VERSION 5.7 ;
BUSBITCHARS "[]" ;
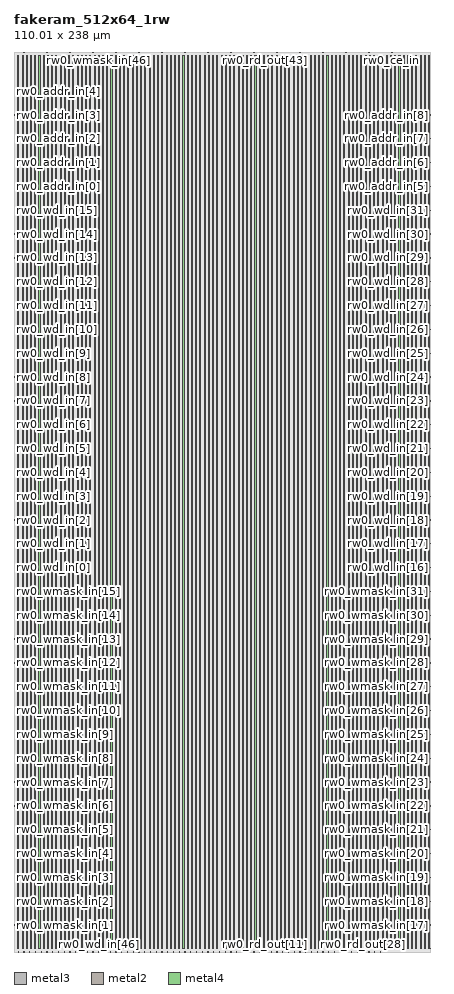
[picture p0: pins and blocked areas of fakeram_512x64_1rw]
MACRO fakeram_512x64_1rw
  FOREIGN fakeram_512x64_1rw 0 0 ;
  SYMMETRY X Y R90 ;
  SIZE 110.010 BY 238.000 ;
  CLASS BLOCK ;
  PIN rw0_wmask_in[0]
    DIRECTION INPUT ;
    USE SIGNAL ;
    SHAPE ABUTMENT ;
    PORT
      LAYER metal3 ;
      RECT 0.000 0.805 0.210 0.875 ;
    END
  END rw0_wmask_in[0]
  PIN rw0_wmask_in[1]
    DIRECTION INPUT ;
    USE SIGNAL ;
    SHAPE ABUTMENT ;
    PORT
      LAYER metal3 ;
      RECT 0.000 7.105 0.210 7.175 ;
    END
  END rw0_wmask_in[1]
  PIN rw0_wmask_in[2]
    DIRECTION INPUT ;
    USE SIGNAL ;
    SHAPE ABUTMENT ;
    PORT
      LAYER metal3 ;
      RECT 0.000 13.405 0.210 13.475 ;
    END
  END rw0_wmask_in[2]
  PIN rw0_wmask_in[3]
    DIRECTION INPUT ;
    USE SIGNAL ;
    SHAPE ABUTMENT ;
    PORT
      LAYER metal3 ;
      RECT 0.000 19.705 0.210 19.775 ;
    END
  END rw0_wmask_in[3]
  PIN rw0_wmask_in[4]
    DIRECTION INPUT ;
    USE SIGNAL ;
    SHAPE ABUTMENT ;
    PORT
      LAYER metal3 ;
      RECT 0.000 26.005 0.210 26.075 ;
    END
  END rw0_wmask_in[4]
  PIN rw0_wmask_in[5]
    DIRECTION INPUT ;
    USE SIGNAL ;
    SHAPE ABUTMENT ;
    PORT
      LAYER metal3 ;
      RECT 0.000 32.305 0.210 32.375 ;
    END
  END rw0_wmask_in[5]
  PIN rw0_wmask_in[6]
    DIRECTION INPUT ;
    USE SIGNAL ;
    SHAPE ABUTMENT ;
    PORT
      LAYER metal3 ;
      RECT 0.000 38.605 0.210 38.675 ;
    END
  END rw0_wmask_in[6]
  PIN rw0_wmask_in[7]
    DIRECTION INPUT ;
    USE SIGNAL ;
    SHAPE ABUTMENT ;
    PORT
      LAYER metal3 ;
      RECT 0.000 44.905 0.210 44.975 ;
    END
  END rw0_wmask_in[7]
  PIN rw0_wmask_in[8]
    DIRECTION INPUT ;
    USE SIGNAL ;
    SHAPE ABUTMENT ;
    PORT
      LAYER metal3 ;
      RECT 0.000 51.205 0.210 51.275 ;
    END
  END rw0_wmask_in[8]
  PIN rw0_wmask_in[9]
    DIRECTION INPUT ;
    USE SIGNAL ;
    SHAPE ABUTMENT ;
    PORT
      LAYER metal3 ;
      RECT 0.000 57.505 0.210 57.575 ;
    END
  END rw0_wmask_in[9]
  PIN rw0_wmask_in[10]
    DIRECTION INPUT ;
    USE SIGNAL ;
    SHAPE ABUTMENT ;
    PORT
      LAYER metal3 ;
      RECT 0.000 63.805 0.210 63.875 ;
    END
  END rw0_wmask_in[10]
  PIN rw0_wmask_in[11]
    DIRECTION INPUT ;
    USE SIGNAL ;
    SHAPE ABUTMENT ;
    PORT
      LAYER metal3 ;
      RECT 0.000 70.105 0.210 70.175 ;
    END
  END rw0_wmask_in[11]
  PIN rw0_wmask_in[12]
    DIRECTION INPUT ;
    USE SIGNAL ;
    SHAPE ABUTMENT ;
    PORT
      LAYER metal3 ;
      RECT 0.000 76.405 0.210 76.475 ;
    END
  END rw0_wmask_in[12]
  PIN rw0_wmask_in[13]
    DIRECTION INPUT ;
    USE SIGNAL ;
    SHAPE ABUTMENT ;
    PORT
      LAYER metal3 ;
      RECT 0.000 82.705 0.210 82.775 ;
    END
  END rw0_wmask_in[13]
  PIN rw0_wmask_in[14]
    DIRECTION INPUT ;
    USE SIGNAL ;
    SHAPE ABUTMENT ;
    PORT
      LAYER metal3 ;
      RECT 0.000 89.005 0.210 89.075 ;
    END
  END rw0_wmask_in[14]
  PIN rw0_wmask_in[15]
    DIRECTION INPUT ;
    USE SIGNAL ;
    SHAPE ABUTMENT ;
    PORT
      LAYER metal3 ;
      RECT 0.000 95.305 0.210 95.375 ;
    END
  END rw0_wmask_in[15]
  PIN rw0_wmask_in[16]
    DIRECTION INPUT ;
    USE SIGNAL ;
    SHAPE ABUTMENT ;
    PORT
      LAYER metal3 ;
      RECT 109.800 0.805 110.010 0.875 ;
    END
  END rw0_wmask_in[16]
  PIN rw0_wmask_in[17]
    DIRECTION INPUT ;
    USE SIGNAL ;
    SHAPE ABUTMENT ;
    PORT
      LAYER metal3 ;
      RECT 109.800 7.105 110.010 7.175 ;
    END
  END rw0_wmask_in[17]
  PIN rw0_wmask_in[18]
    DIRECTION INPUT ;
    USE SIGNAL ;
    SHAPE ABUTMENT ;
    PORT
      LAYER metal3 ;
      RECT 109.800 13.405 110.010 13.475 ;
    END
  END rw0_wmask_in[18]
  PIN rw0_wmask_in[19]
    DIRECTION INPUT ;
    USE SIGNAL ;
    SHAPE ABUTMENT ;
    PORT
      LAYER metal3 ;
      RECT 109.800 19.705 110.010 19.775 ;
    END
  END rw0_wmask_in[19]
  PIN rw0_wmask_in[20]
    DIRECTION INPUT ;
    USE SIGNAL ;
    SHAPE ABUTMENT ;
    PORT
      LAYER metal3 ;
      RECT 109.800 26.005 110.010 26.075 ;
    END
  END rw0_wmask_in[20]
  PIN rw0_wmask_in[21]
    DIRECTION INPUT ;
    USE SIGNAL ;
    SHAPE ABUTMENT ;
    PORT
      LAYER metal3 ;
      RECT 109.800 32.305 110.010 32.375 ;
    END
  END rw0_wmask_in[21]
  PIN rw0_wmask_in[22]
    DIRECTION INPUT ;
    USE SIGNAL ;
    SHAPE ABUTMENT ;
    PORT
      LAYER metal3 ;
      RECT 109.800 38.605 110.010 38.675 ;
    END
  END rw0_wmask_in[22]
  PIN rw0_wmask_in[23]
    DIRECTION INPUT ;
    USE SIGNAL ;
    SHAPE ABUTMENT ;
    PORT
      LAYER metal3 ;
      RECT 109.800 44.905 110.010 44.975 ;
    END
  END rw0_wmask_in[23]
  PIN rw0_wmask_in[24]
    DIRECTION INPUT ;
    USE SIGNAL ;
    SHAPE ABUTMENT ;
    PORT
      LAYER metal3 ;
      RECT 109.800 51.205 110.010 51.275 ;
    END
  END rw0_wmask_in[24]
  PIN rw0_wmask_in[25]
    DIRECTION INPUT ;
    USE SIGNAL ;
    SHAPE ABUTMENT ;
    PORT
      LAYER metal3 ;
      RECT 109.800 57.505 110.010 57.575 ;
    END
  END rw0_wmask_in[25]
  PIN rw0_wmask_in[26]
    DIRECTION INPUT ;
    USE SIGNAL ;
    SHAPE ABUTMENT ;
    PORT
      LAYER metal3 ;
      RECT 109.800 63.805 110.010 63.875 ;
    END
  END rw0_wmask_in[26]
  PIN rw0_wmask_in[27]
    DIRECTION INPUT ;
    USE SIGNAL ;
    SHAPE ABUTMENT ;
    PORT
      LAYER metal3 ;
      RECT 109.800 70.105 110.010 70.175 ;
    END
  END rw0_wmask_in[27]
  PIN rw0_wmask_in[28]
    DIRECTION INPUT ;
    USE SIGNAL ;
    SHAPE ABUTMENT ;
    PORT
      LAYER metal3 ;
      RECT 109.800 76.405 110.010 76.475 ;
    END
  END rw0_wmask_in[28]
  PIN rw0_wmask_in[29]
    DIRECTION INPUT ;
    USE SIGNAL ;
    SHAPE ABUTMENT ;
    PORT
      LAYER metal3 ;
      RECT 109.800 82.705 110.010 82.775 ;
    END
  END rw0_wmask_in[29]
  PIN rw0_wmask_in[30]
    DIRECTION INPUT ;
    USE SIGNAL ;
    SHAPE ABUTMENT ;
    PORT
      LAYER metal3 ;
      RECT 109.800 89.005 110.010 89.075 ;
    END
  END rw0_wmask_in[30]
  PIN rw0_wmask_in[31]
    DIRECTION INPUT ;
    USE SIGNAL ;
    SHAPE ABUTMENT ;
    PORT
      LAYER metal3 ;
      RECT 109.800 95.305 110.010 95.375 ;
    END
  END rw0_wmask_in[31]
  PIN rw0_wmask_in[32]
    DIRECTION INPUT ;
    USE SIGNAL ;
    SHAPE ABUTMENT ;
    PORT
      LAYER metal2 ;
      RECT 1.105 237.790 1.175 238.000 ;
    END
  END rw0_wmask_in[32]
  PIN rw0_wmask_in[33]
    DIRECTION INPUT ;
    USE SIGNAL ;
    SHAPE ABUTMENT ;
    PORT
      LAYER metal2 ;
      RECT 2.625 237.790 2.695 238.000 ;
    END
  END rw0_wmask_in[33]
  PIN rw0_wmask_in[34]
    DIRECTION INPUT ;
    USE SIGNAL ;
    SHAPE ABUTMENT ;
    PORT
      LAYER metal2 ;
      RECT 4.145 237.790 4.215 238.000 ;
    END
  END rw0_wmask_in[34]
  PIN rw0_wmask_in[35]
    DIRECTION INPUT ;
    USE SIGNAL ;
    SHAPE ABUTMENT ;
    PORT
      LAYER metal2 ;
      RECT 5.665 237.790 5.735 238.000 ;
    END
  END rw0_wmask_in[35]
  PIN rw0_wmask_in[36]
    DIRECTION INPUT ;
    USE SIGNAL ;
    SHAPE ABUTMENT ;
    PORT
      LAYER metal2 ;
      RECT 7.185 237.790 7.255 238.000 ;
    END
  END rw0_wmask_in[36]
  PIN rw0_wmask_in[37]
    DIRECTION INPUT ;
    USE SIGNAL ;
    SHAPE ABUTMENT ;
    PORT
      LAYER metal2 ;
      RECT 8.705 237.790 8.775 238.000 ;
    END
  END rw0_wmask_in[37]
  PIN rw0_wmask_in[38]
    DIRECTION INPUT ;
    USE SIGNAL ;
    SHAPE ABUTMENT ;
    PORT
      LAYER metal2 ;
      RECT 10.225 237.790 10.295 238.000 ;
    END
  END rw0_wmask_in[38]
  PIN rw0_wmask_in[39]
    DIRECTION INPUT ;
    USE SIGNAL ;
    SHAPE ABUTMENT ;
    PORT
      LAYER metal2 ;
      RECT 11.745 237.790 11.815 238.000 ;
    END
  END rw0_wmask_in[39]
  PIN rw0_wmask_in[40]
    DIRECTION INPUT ;
    USE SIGNAL ;
    SHAPE ABUTMENT ;
    PORT
      LAYER metal2 ;
      RECT 13.265 237.790 13.335 238.000 ;
    END
  END rw0_wmask_in[40]
  PIN rw0_wmask_in[41]
    DIRECTION INPUT ;
    USE SIGNAL ;
    SHAPE ABUTMENT ;
    PORT
      LAYER metal2 ;
      RECT 14.785 237.790 14.855 238.000 ;
    END
  END rw0_wmask_in[41]
  PIN rw0_wmask_in[42]
    DIRECTION INPUT ;
    USE SIGNAL ;
    SHAPE ABUTMENT ;
    PORT
      LAYER metal2 ;
      RECT 16.305 237.790 16.375 238.000 ;
    END
  END rw0_wmask_in[42]
  PIN rw0_wmask_in[43]
    DIRECTION INPUT ;
    USE SIGNAL ;
    SHAPE ABUTMENT ;
    PORT
      LAYER metal2 ;
      RECT 17.825 237.790 17.895 238.000 ;
    END
  END rw0_wmask_in[43]
  PIN rw0_wmask_in[44]
    DIRECTION INPUT ;
    USE SIGNAL ;
    SHAPE ABUTMENT ;
    PORT
      LAYER metal2 ;
      RECT 19.345 237.790 19.415 238.000 ;
    END
  END rw0_wmask_in[44]
  PIN rw0_wmask_in[45]
    DIRECTION INPUT ;
    USE SIGNAL ;
    SHAPE ABUTMENT ;
    PORT
      LAYER metal2 ;
      RECT 20.865 237.790 20.935 238.000 ;
    END
  END rw0_wmask_in[45]
  PIN rw0_wmask_in[46]
    DIRECTION INPUT ;
    USE SIGNAL ;
    SHAPE ABUTMENT ;
    PORT
      LAYER metal2 ;
      RECT 22.385 237.790 22.455 238.000 ;
    END
  END rw0_wmask_in[46]
  PIN rw0_wmask_in[47]
    DIRECTION INPUT ;
    USE SIGNAL ;
    SHAPE ABUTMENT ;
    PORT
      LAYER metal2 ;
      RECT 23.905 237.790 23.975 238.000 ;
    END
  END rw0_wmask_in[47]
  PIN rw0_wmask_in[48]
    DIRECTION INPUT ;
    USE SIGNAL ;
    SHAPE ABUTMENT ;
    PORT
      LAYER metal2 ;
      RECT 25.425 237.790 25.495 238.000 ;
    END
  END rw0_wmask_in[48]
  PIN rw0_wmask_in[49]
    DIRECTION INPUT ;
    USE SIGNAL ;
    SHAPE ABUTMENT ;
    PORT
      LAYER metal2 ;
      RECT 26.945 237.790 27.015 238.000 ;
    END
  END rw0_wmask_in[49]
  PIN rw0_wmask_in[50]
    DIRECTION INPUT ;
    USE SIGNAL ;
    SHAPE ABUTMENT ;
    PORT
      LAYER metal2 ;
      RECT 28.465 237.790 28.535 238.000 ;
    END
  END rw0_wmask_in[50]
  PIN rw0_wmask_in[51]
    DIRECTION INPUT ;
    USE SIGNAL ;
    SHAPE ABUTMENT ;
    PORT
      LAYER metal2 ;
      RECT 29.985 237.790 30.055 238.000 ;
    END
  END rw0_wmask_in[51]
  PIN rw0_wmask_in[52]
    DIRECTION INPUT ;
    USE SIGNAL ;
    SHAPE ABUTMENT ;
    PORT
      LAYER metal2 ;
      RECT 31.505 237.790 31.575 238.000 ;
    END
  END rw0_wmask_in[52]
  PIN rw0_wmask_in[53]
    DIRECTION INPUT ;
    USE SIGNAL ;
    SHAPE ABUTMENT ;
    PORT
      LAYER metal2 ;
      RECT 33.025 237.790 33.095 238.000 ;
    END
  END rw0_wmask_in[53]
  PIN rw0_wmask_in[54]
    DIRECTION INPUT ;
    USE SIGNAL ;
    SHAPE ABUTMENT ;
    PORT
      LAYER metal2 ;
      RECT 34.545 237.790 34.615 238.000 ;
    END
  END rw0_wmask_in[54]
  PIN rw0_wmask_in[55]
    DIRECTION INPUT ;
    USE SIGNAL ;
    SHAPE ABUTMENT ;
    PORT
      LAYER metal2 ;
      RECT 36.065 237.790 36.135 238.000 ;
    END
  END rw0_wmask_in[55]
  PIN rw0_wmask_in[56]
    DIRECTION INPUT ;
    USE SIGNAL ;
    SHAPE ABUTMENT ;
    PORT
      LAYER metal2 ;
      RECT 37.585 237.790 37.655 238.000 ;
    END
  END rw0_wmask_in[56]
  PIN rw0_wmask_in[57]
    DIRECTION INPUT ;
    USE SIGNAL ;
    SHAPE ABUTMENT ;
    PORT
      LAYER metal2 ;
      RECT 39.105 237.790 39.175 238.000 ;
    END
  END rw0_wmask_in[57]
  PIN rw0_wmask_in[58]
    DIRECTION INPUT ;
    USE SIGNAL ;
    SHAPE ABUTMENT ;
    PORT
      LAYER metal2 ;
      RECT 40.625 237.790 40.695 238.000 ;
    END
  END rw0_wmask_in[58]
  PIN rw0_wmask_in[59]
    DIRECTION INPUT ;
    USE SIGNAL ;
    SHAPE ABUTMENT ;
    PORT
      LAYER metal2 ;
      RECT 42.145 237.790 42.215 238.000 ;
    END
  END rw0_wmask_in[59]
  PIN rw0_wmask_in[60]
    DIRECTION INPUT ;
    USE SIGNAL ;
    SHAPE ABUTMENT ;
    PORT
      LAYER metal2 ;
      RECT 43.665 237.790 43.735 238.000 ;
    END
  END rw0_wmask_in[60]
  PIN rw0_wmask_in[61]
    DIRECTION INPUT ;
    USE SIGNAL ;
    SHAPE ABUTMENT ;
    PORT
      LAYER metal2 ;
      RECT 45.185 237.790 45.255 238.000 ;
    END
  END rw0_wmask_in[61]
  PIN rw0_wmask_in[62]
    DIRECTION INPUT ;
    USE SIGNAL ;
    SHAPE ABUTMENT ;
    PORT
      LAYER metal2 ;
      RECT 46.705 237.790 46.775 238.000 ;
    END
  END rw0_wmask_in[62]
  PIN rw0_wmask_in[63]
    DIRECTION INPUT ;
    USE SIGNAL ;
    SHAPE ABUTMENT ;
    PORT
      LAYER metal2 ;
      RECT 48.225 237.790 48.295 238.000 ;
    END
  END rw0_wmask_in[63]
  PIN rw0_wd_in[0]
    DIRECTION INPUT ;
    USE SIGNAL ;
    SHAPE ABUTMENT ;
    PORT
      LAYER metal3 ;
      RECT 0.000 101.605 0.210 101.675 ;
    END
  END rw0_wd_in[0]
  PIN rw0_wd_in[1]
    DIRECTION INPUT ;
    USE SIGNAL ;
    SHAPE ABUTMENT ;
    PORT
      LAYER metal3 ;
      RECT 0.000 107.905 0.210 107.975 ;
    END
  END rw0_wd_in[1]
  PIN rw0_wd_in[2]
    DIRECTION INPUT ;
    USE SIGNAL ;
    SHAPE ABUTMENT ;
    PORT
      LAYER metal3 ;
      RECT 0.000 114.205 0.210 114.275 ;
    END
  END rw0_wd_in[2]
  PIN rw0_wd_in[3]
    DIRECTION INPUT ;
    USE SIGNAL ;
    SHAPE ABUTMENT ;
    PORT
      LAYER metal3 ;
      RECT 0.000 120.505 0.210 120.575 ;
    END
  END rw0_wd_in[3]
  PIN rw0_wd_in[4]
    DIRECTION INPUT ;
    USE SIGNAL ;
    SHAPE ABUTMENT ;
    PORT
      LAYER metal3 ;
      RECT 0.000 126.805 0.210 126.875 ;
    END
  END rw0_wd_in[4]
  PIN rw0_wd_in[5]
    DIRECTION INPUT ;
    USE SIGNAL ;
    SHAPE ABUTMENT ;
    PORT
      LAYER metal3 ;
      RECT 0.000 133.105 0.210 133.175 ;
    END
  END rw0_wd_in[5]
  PIN rw0_wd_in[6]
    DIRECTION INPUT ;
    USE SIGNAL ;
    SHAPE ABUTMENT ;
    PORT
      LAYER metal3 ;
      RECT 0.000 139.405 0.210 139.475 ;
    END
  END rw0_wd_in[6]
  PIN rw0_wd_in[7]
    DIRECTION INPUT ;
    USE SIGNAL ;
    SHAPE ABUTMENT ;
    PORT
      LAYER metal3 ;
      RECT 0.000 145.705 0.210 145.775 ;
    END
  END rw0_wd_in[7]
  PIN rw0_wd_in[8]
    DIRECTION INPUT ;
    USE SIGNAL ;
    SHAPE ABUTMENT ;
    PORT
      LAYER metal3 ;
      RECT 0.000 152.005 0.210 152.075 ;
    END
  END rw0_wd_in[8]
  PIN rw0_wd_in[9]
    DIRECTION INPUT ;
    USE SIGNAL ;
    SHAPE ABUTMENT ;
    PORT
      LAYER metal3 ;
      RECT 0.000 158.305 0.210 158.375 ;
    END
  END rw0_wd_in[9]
  PIN rw0_wd_in[10]
    DIRECTION INPUT ;
    USE SIGNAL ;
    SHAPE ABUTMENT ;
    PORT
      LAYER metal3 ;
      RECT 0.000 164.605 0.210 164.675 ;
    END
  END rw0_wd_in[10]
  PIN rw0_wd_in[11]
    DIRECTION INPUT ;
    USE SIGNAL ;
    SHAPE ABUTMENT ;
    PORT
      LAYER metal3 ;
      RECT 0.000 170.905 0.210 170.975 ;
    END
  END rw0_wd_in[11]
  PIN rw0_wd_in[12]
    DIRECTION INPUT ;
    USE SIGNAL ;
    SHAPE ABUTMENT ;
    PORT
      LAYER metal3 ;
      RECT 0.000 177.205 0.210 177.275 ;
    END
  END rw0_wd_in[12]
  PIN rw0_wd_in[13]
    DIRECTION INPUT ;
    USE SIGNAL ;
    SHAPE ABUTMENT ;
    PORT
      LAYER metal3 ;
      RECT 0.000 183.505 0.210 183.575 ;
    END
  END rw0_wd_in[13]
  PIN rw0_wd_in[14]
    DIRECTION INPUT ;
    USE SIGNAL ;
    SHAPE ABUTMENT ;
    PORT
      LAYER metal3 ;
      RECT 0.000 189.805 0.210 189.875 ;
    END
  END rw0_wd_in[14]
  PIN rw0_wd_in[15]
    DIRECTION INPUT ;
    USE SIGNAL ;
    SHAPE ABUTMENT ;
    PORT
      LAYER metal3 ;
      RECT 0.000 196.105 0.210 196.175 ;
    END
  END rw0_wd_in[15]
  PIN rw0_wd_in[16]
    DIRECTION INPUT ;
    USE SIGNAL ;
    SHAPE ABUTMENT ;
    PORT
      LAYER metal3 ;
      RECT 109.800 101.605 110.010 101.675 ;
    END
  END rw0_wd_in[16]
  PIN rw0_wd_in[17]
    DIRECTION INPUT ;
    USE SIGNAL ;
    SHAPE ABUTMENT ;
    PORT
      LAYER metal3 ;
      RECT 109.800 107.905 110.010 107.975 ;
    END
  END rw0_wd_in[17]
  PIN rw0_wd_in[18]
    DIRECTION INPUT ;
    USE SIGNAL ;
    SHAPE ABUTMENT ;
    PORT
      LAYER metal3 ;
      RECT 109.800 114.205 110.010 114.275 ;
    END
  END rw0_wd_in[18]
  PIN rw0_wd_in[19]
    DIRECTION INPUT ;
    USE SIGNAL ;
    SHAPE ABUTMENT ;
    PORT
      LAYER metal3 ;
      RECT 109.800 120.505 110.010 120.575 ;
    END
  END rw0_wd_in[19]
  PIN rw0_wd_in[20]
    DIRECTION INPUT ;
    USE SIGNAL ;
    SHAPE ABUTMENT ;
    PORT
      LAYER metal3 ;
      RECT 109.800 126.805 110.010 126.875 ;
    END
  END rw0_wd_in[20]
  PIN rw0_wd_in[21]
    DIRECTION INPUT ;
    USE SIGNAL ;
    SHAPE ABUTMENT ;
    PORT
      LAYER metal3 ;
      RECT 109.800 133.105 110.010 133.175 ;
    END
  END rw0_wd_in[21]
  PIN rw0_wd_in[22]
    DIRECTION INPUT ;
    USE SIGNAL ;
    SHAPE ABUTMENT ;
    PORT
      LAYER metal3 ;
      RECT 109.800 139.405 110.010 139.475 ;
    END
  END rw0_wd_in[22]
  PIN rw0_wd_in[23]
    DIRECTION INPUT ;
    USE SIGNAL ;
    SHAPE ABUTMENT ;
    PORT
      LAYER metal3 ;
      RECT 109.800 145.705 110.010 145.775 ;
    END
  END rw0_wd_in[23]
  PIN rw0_wd_in[24]
    DIRECTION INPUT ;
    USE SIGNAL ;
    SHAPE ABUTMENT ;
    PORT
      LAYER metal3 ;
      RECT 109.800 152.005 110.010 152.075 ;
    END
  END rw0_wd_in[24]
  PIN rw0_wd_in[25]
    DIRECTION INPUT ;
    USE SIGNAL ;
    SHAPE ABUTMENT ;
    PORT
      LAYER metal3 ;
      RECT 109.800 158.305 110.010 158.375 ;
    END
  END rw0_wd_in[25]
  PIN rw0_wd_in[26]
    DIRECTION INPUT ;
    USE SIGNAL ;
    SHAPE ABUTMENT ;
    PORT
      LAYER metal3 ;
      RECT 109.800 164.605 110.010 164.675 ;
    END
  END rw0_wd_in[26]
  PIN rw0_wd_in[27]
    DIRECTION INPUT ;
    USE SIGNAL ;
    SHAPE ABUTMENT ;
    PORT
      LAYER metal3 ;
      RECT 109.800 170.905 110.010 170.975 ;
    END
  END rw0_wd_in[27]
  PIN rw0_wd_in[28]
    DIRECTION INPUT ;
    USE SIGNAL ;
    SHAPE ABUTMENT ;
    PORT
      LAYER metal3 ;
      RECT 109.800 177.205 110.010 177.275 ;
    END
  END rw0_wd_in[28]
  PIN rw0_wd_in[29]
    DIRECTION INPUT ;
    USE SIGNAL ;
    SHAPE ABUTMENT ;
    PORT
      LAYER metal3 ;
      RECT 109.800 183.505 110.010 183.575 ;
    END
  END rw0_wd_in[29]
  PIN rw0_wd_in[30]
    DIRECTION INPUT ;
    USE SIGNAL ;
    SHAPE ABUTMENT ;
    PORT
      LAYER metal3 ;
      RECT 109.800 189.805 110.010 189.875 ;
    END
  END rw0_wd_in[30]
  PIN rw0_wd_in[31]
    DIRECTION INPUT ;
    USE SIGNAL ;
    SHAPE ABUTMENT ;
    PORT
      LAYER metal3 ;
      RECT 109.800 196.105 110.010 196.175 ;
    END
  END rw0_wd_in[31]
  PIN rw0_wd_in[32]
    DIRECTION INPUT ;
    USE SIGNAL ;
    SHAPE ABUTMENT ;
    PORT
      LAYER metal2 ;
      RECT 1.105 0.000 1.175 0.210 ;
    END
  END rw0_wd_in[32]
  PIN rw0_wd_in[33]
    DIRECTION INPUT ;
    USE SIGNAL ;
    SHAPE ABUTMENT ;
    PORT
      LAYER metal2 ;
      RECT 2.625 0.000 2.695 0.210 ;
    END
  END rw0_wd_in[33]
  PIN rw0_wd_in[34]
    DIRECTION INPUT ;
    USE SIGNAL ;
    SHAPE ABUTMENT ;
    PORT
      LAYER metal2 ;
      RECT 4.145 0.000 4.215 0.210 ;
    END
  END rw0_wd_in[34]
  PIN rw0_wd_in[35]
    DIRECTION INPUT ;
    USE SIGNAL ;
    SHAPE ABUTMENT ;
    PORT
      LAYER metal2 ;
      RECT 5.665 0.000 5.735 0.210 ;
    END
  END rw0_wd_in[35]
  PIN rw0_wd_in[36]
    DIRECTION INPUT ;
    USE SIGNAL ;
    SHAPE ABUTMENT ;
    PORT
      LAYER metal2 ;
      RECT 7.185 0.000 7.255 0.210 ;
    END
  END rw0_wd_in[36]
  PIN rw0_wd_in[37]
    DIRECTION INPUT ;
    USE SIGNAL ;
    SHAPE ABUTMENT ;
    PORT
      LAYER metal2 ;
      RECT 8.705 0.000 8.775 0.210 ;
    END
  END rw0_wd_in[37]
  PIN rw0_wd_in[38]
    DIRECTION INPUT ;
    USE SIGNAL ;
    SHAPE ABUTMENT ;
    PORT
      LAYER metal2 ;
      RECT 10.225 0.000 10.295 0.210 ;
    END
  END rw0_wd_in[38]
  PIN rw0_wd_in[39]
    DIRECTION INPUT ;
    USE SIGNAL ;
    SHAPE ABUTMENT ;
    PORT
      LAYER metal2 ;
      RECT 11.745 0.000 11.815 0.210 ;
    END
  END rw0_wd_in[39]
  PIN rw0_wd_in[40]
    DIRECTION INPUT ;
    USE SIGNAL ;
    SHAPE ABUTMENT ;
    PORT
      LAYER metal2 ;
      RECT 13.265 0.000 13.335 0.210 ;
    END
  END rw0_wd_in[40]
  PIN rw0_wd_in[41]
    DIRECTION INPUT ;
    USE SIGNAL ;
    SHAPE ABUTMENT ;
    PORT
      LAYER metal2 ;
      RECT 14.785 0.000 14.855 0.210 ;
    END
  END rw0_wd_in[41]
  PIN rw0_wd_in[42]
    DIRECTION INPUT ;
    USE SIGNAL ;
    SHAPE ABUTMENT ;
    PORT
      LAYER metal2 ;
      RECT 16.305 0.000 16.375 0.210 ;
    END
  END rw0_wd_in[42]
  PIN rw0_wd_in[43]
    DIRECTION INPUT ;
    USE SIGNAL ;
    SHAPE ABUTMENT ;
    PORT
      LAYER metal2 ;
      RECT 17.825 0.000 17.895 0.210 ;
    END
  END rw0_wd_in[43]
  PIN rw0_wd_in[44]
    DIRECTION INPUT ;
    USE SIGNAL ;
    SHAPE ABUTMENT ;
    PORT
      LAYER metal2 ;
      RECT 19.345 0.000 19.415 0.210 ;
    END
  END rw0_wd_in[44]
  PIN rw0_wd_in[45]
    DIRECTION INPUT ;
    USE SIGNAL ;
    SHAPE ABUTMENT ;
    PORT
      LAYER metal2 ;
      RECT 20.865 0.000 20.935 0.210 ;
    END
  END rw0_wd_in[45]
  PIN rw0_wd_in[46]
    DIRECTION INPUT ;
    USE SIGNAL ;
    SHAPE ABUTMENT ;
    PORT
      LAYER metal2 ;
      RECT 22.385 0.000 22.455 0.210 ;
    END
  END rw0_wd_in[46]
  PIN rw0_wd_in[47]
    DIRECTION INPUT ;
    USE SIGNAL ;
    SHAPE ABUTMENT ;
    PORT
      LAYER metal2 ;
      RECT 23.905 0.000 23.975 0.210 ;
    END
  END rw0_wd_in[47]
  PIN rw0_wd_in[48]
    DIRECTION INPUT ;
    USE SIGNAL ;
    SHAPE ABUTMENT ;
    PORT
      LAYER metal2 ;
      RECT 25.425 0.000 25.495 0.210 ;
    END
  END rw0_wd_in[48]
  PIN rw0_wd_in[49]
    DIRECTION INPUT ;
    USE SIGNAL ;
    SHAPE ABUTMENT ;
    PORT
      LAYER metal2 ;
      RECT 26.945 0.000 27.015 0.210 ;
    END
  END rw0_wd_in[49]
  PIN rw0_wd_in[50]
    DIRECTION INPUT ;
    USE SIGNAL ;
    SHAPE ABUTMENT ;
    PORT
      LAYER metal2 ;
      RECT 28.465 0.000 28.535 0.210 ;
    END
  END rw0_wd_in[50]
  PIN rw0_wd_in[51]
    DIRECTION INPUT ;
    USE SIGNAL ;
    SHAPE ABUTMENT ;
    PORT
      LAYER metal2 ;
      RECT 29.985 0.000 30.055 0.210 ;
    END
  END rw0_wd_in[51]
  PIN rw0_wd_in[52]
    DIRECTION INPUT ;
    USE SIGNAL ;
    SHAPE ABUTMENT ;
    PORT
      LAYER metal2 ;
      RECT 31.505 0.000 31.575 0.210 ;
    END
  END rw0_wd_in[52]
  PIN rw0_wd_in[53]
    DIRECTION INPUT ;
    USE SIGNAL ;
    SHAPE ABUTMENT ;
    PORT
      LAYER metal2 ;
      RECT 33.025 0.000 33.095 0.210 ;
    END
  END rw0_wd_in[53]
  PIN rw0_wd_in[54]
    DIRECTION INPUT ;
    USE SIGNAL ;
    SHAPE ABUTMENT ;
    PORT
      LAYER metal2 ;
      RECT 34.545 0.000 34.615 0.210 ;
    END
  END rw0_wd_in[54]
  PIN rw0_wd_in[55]
    DIRECTION INPUT ;
    USE SIGNAL ;
    SHAPE ABUTMENT ;
    PORT
      LAYER metal2 ;
      RECT 36.065 0.000 36.135 0.210 ;
    END
  END rw0_wd_in[55]
  PIN rw0_wd_in[56]
    DIRECTION INPUT ;
    USE SIGNAL ;
    SHAPE ABUTMENT ;
    PORT
      LAYER metal2 ;
      RECT 37.585 0.000 37.655 0.210 ;
    END
  END rw0_wd_in[56]
  PIN rw0_wd_in[57]
    DIRECTION INPUT ;
    USE SIGNAL ;
    SHAPE ABUTMENT ;
    PORT
      LAYER metal2 ;
      RECT 39.105 0.000 39.175 0.210 ;
    END
  END rw0_wd_in[57]
  PIN rw0_wd_in[58]
    DIRECTION INPUT ;
    USE SIGNAL ;
    SHAPE ABUTMENT ;
    PORT
      LAYER metal2 ;
      RECT 40.625 0.000 40.695 0.210 ;
    END
  END rw0_wd_in[58]
  PIN rw0_wd_in[59]
    DIRECTION INPUT ;
    USE SIGNAL ;
    SHAPE ABUTMENT ;
    PORT
      LAYER metal2 ;
      RECT 42.145 0.000 42.215 0.210 ;
    END
  END rw0_wd_in[59]
  PIN rw0_wd_in[60]
    DIRECTION INPUT ;
    USE SIGNAL ;
    SHAPE ABUTMENT ;
    PORT
      LAYER metal2 ;
      RECT 43.665 0.000 43.735 0.210 ;
    END
  END rw0_wd_in[60]
  PIN rw0_wd_in[61]
    DIRECTION INPUT ;
    USE SIGNAL ;
    SHAPE ABUTMENT ;
    PORT
      LAYER metal2 ;
      RECT 45.185 0.000 45.255 0.210 ;
    END
  END rw0_wd_in[61]
  PIN rw0_wd_in[62]
    DIRECTION INPUT ;
    USE SIGNAL ;
    SHAPE ABUTMENT ;
    PORT
      LAYER metal2 ;
      RECT 46.705 0.000 46.775 0.210 ;
    END
  END rw0_wd_in[62]
  PIN rw0_wd_in[63]
    DIRECTION INPUT ;
    USE SIGNAL ;
    SHAPE ABUTMENT ;
    PORT
      LAYER metal2 ;
      RECT 48.225 0.000 48.295 0.210 ;
    END
  END rw0_wd_in[63]
  PIN rw0_rd_out[0]
    DIRECTION OUTPUT ;
    USE SIGNAL ;
    SHAPE ABUTMENT ;
    PORT
      LAYER metal2 ;
      RECT 49.745 0.000 49.815 0.210 ;
    END
  END rw0_rd_out[0]
  PIN rw0_rd_out[1]
    DIRECTION OUTPUT ;
    USE SIGNAL ;
    SHAPE ABUTMENT ;
    PORT
      LAYER metal2 ;
      RECT 51.265 0.000 51.335 0.210 ;
    END
  END rw0_rd_out[1]
  PIN rw0_rd_out[2]
    DIRECTION OUTPUT ;
    USE SIGNAL ;
    SHAPE ABUTMENT ;
    PORT
      LAYER metal2 ;
      RECT 52.785 0.000 52.855 0.210 ;
    END
  END rw0_rd_out[2]
  PIN rw0_rd_out[3]
    DIRECTION OUTPUT ;
    USE SIGNAL ;
    SHAPE ABUTMENT ;
    PORT
      LAYER metal2 ;
      RECT 54.305 0.000 54.375 0.210 ;
    END
  END rw0_rd_out[3]
  PIN rw0_rd_out[4]
    DIRECTION OUTPUT ;
    USE SIGNAL ;
    SHAPE ABUTMENT ;
    PORT
      LAYER metal2 ;
      RECT 55.825 0.000 55.895 0.210 ;
    END
  END rw0_rd_out[4]
  PIN rw0_rd_out[5]
    DIRECTION OUTPUT ;
    USE SIGNAL ;
    SHAPE ABUTMENT ;
    PORT
      LAYER metal2 ;
      RECT 57.345 0.000 57.415 0.210 ;
    END
  END rw0_rd_out[5]
  PIN rw0_rd_out[6]
    DIRECTION OUTPUT ;
    USE SIGNAL ;
    SHAPE ABUTMENT ;
    PORT
      LAYER metal2 ;
      RECT 58.865 0.000 58.935 0.210 ;
    END
  END rw0_rd_out[6]
  PIN rw0_rd_out[7]
    DIRECTION OUTPUT ;
    USE SIGNAL ;
    SHAPE ABUTMENT ;
    PORT
      LAYER metal2 ;
      RECT 60.385 0.000 60.455 0.210 ;
    END
  END rw0_rd_out[7]
  PIN rw0_rd_out[8]
    DIRECTION OUTPUT ;
    USE SIGNAL ;
    SHAPE ABUTMENT ;
    PORT
      LAYER metal2 ;
      RECT 61.905 0.000 61.975 0.210 ;
    END
  END rw0_rd_out[8]
  PIN rw0_rd_out[9]
    DIRECTION OUTPUT ;
    USE SIGNAL ;
    SHAPE ABUTMENT ;
    PORT
      LAYER metal2 ;
      RECT 63.425 0.000 63.495 0.210 ;
    END
  END rw0_rd_out[9]
  PIN rw0_rd_out[10]
    DIRECTION OUTPUT ;
    USE SIGNAL ;
    SHAPE ABUTMENT ;
    PORT
      LAYER metal2 ;
      RECT 64.945 0.000 65.015 0.210 ;
    END
  END rw0_rd_out[10]
  PIN rw0_rd_out[11]
    DIRECTION OUTPUT ;
    USE SIGNAL ;
    SHAPE ABUTMENT ;
    PORT
      LAYER metal2 ;
      RECT 66.465 0.000 66.535 0.210 ;
    END
  END rw0_rd_out[11]
  PIN rw0_rd_out[12]
    DIRECTION OUTPUT ;
    USE SIGNAL ;
    SHAPE ABUTMENT ;
    PORT
      LAYER metal2 ;
      RECT 67.985 0.000 68.055 0.210 ;
    END
  END rw0_rd_out[12]
  PIN rw0_rd_out[13]
    DIRECTION OUTPUT ;
    USE SIGNAL ;
    SHAPE ABUTMENT ;
    PORT
      LAYER metal2 ;
      RECT 69.505 0.000 69.575 0.210 ;
    END
  END rw0_rd_out[13]
  PIN rw0_rd_out[14]
    DIRECTION OUTPUT ;
    USE SIGNAL ;
    SHAPE ABUTMENT ;
    PORT
      LAYER metal2 ;
      RECT 71.025 0.000 71.095 0.210 ;
    END
  END rw0_rd_out[14]
  PIN rw0_rd_out[15]
    DIRECTION OUTPUT ;
    USE SIGNAL ;
    SHAPE ABUTMENT ;
    PORT
      LAYER metal2 ;
      RECT 72.545 0.000 72.615 0.210 ;
    END
  END rw0_rd_out[15]
  PIN rw0_rd_out[16]
    DIRECTION OUTPUT ;
    USE SIGNAL ;
    SHAPE ABUTMENT ;
    PORT
      LAYER metal2 ;
      RECT 74.065 0.000 74.135 0.210 ;
    END
  END rw0_rd_out[16]
  PIN rw0_rd_out[17]
    DIRECTION OUTPUT ;
    USE SIGNAL ;
    SHAPE ABUTMENT ;
    PORT
      LAYER metal2 ;
      RECT 75.585 0.000 75.655 0.210 ;
    END
  END rw0_rd_out[17]
  PIN rw0_rd_out[18]
    DIRECTION OUTPUT ;
    USE SIGNAL ;
    SHAPE ABUTMENT ;
    PORT
      LAYER metal2 ;
      RECT 77.105 0.000 77.175 0.210 ;
    END
  END rw0_rd_out[18]
  PIN rw0_rd_out[19]
    DIRECTION OUTPUT ;
    USE SIGNAL ;
    SHAPE ABUTMENT ;
    PORT
      LAYER metal2 ;
      RECT 78.625 0.000 78.695 0.210 ;
    END
  END rw0_rd_out[19]
  PIN rw0_rd_out[20]
    DIRECTION OUTPUT ;
    USE SIGNAL ;
    SHAPE ABUTMENT ;
    PORT
      LAYER metal2 ;
      RECT 80.145 0.000 80.215 0.210 ;
    END
  END rw0_rd_out[20]
  PIN rw0_rd_out[21]
    DIRECTION OUTPUT ;
    USE SIGNAL ;
    SHAPE ABUTMENT ;
    PORT
      LAYER metal2 ;
      RECT 81.665 0.000 81.735 0.210 ;
    END
  END rw0_rd_out[21]
  PIN rw0_rd_out[22]
    DIRECTION OUTPUT ;
    USE SIGNAL ;
    SHAPE ABUTMENT ;
    PORT
      LAYER metal2 ;
      RECT 83.185 0.000 83.255 0.210 ;
    END
  END rw0_rd_out[22]
  PIN rw0_rd_out[23]
    DIRECTION OUTPUT ;
    USE SIGNAL ;
    SHAPE ABUTMENT ;
    PORT
      LAYER metal2 ;
      RECT 84.705 0.000 84.775 0.210 ;
    END
  END rw0_rd_out[23]
  PIN rw0_rd_out[24]
    DIRECTION OUTPUT ;
    USE SIGNAL ;
    SHAPE ABUTMENT ;
    PORT
      LAYER metal2 ;
      RECT 86.225 0.000 86.295 0.210 ;
    END
  END rw0_rd_out[24]
  PIN rw0_rd_out[25]
    DIRECTION OUTPUT ;
    USE SIGNAL ;
    SHAPE ABUTMENT ;
    PORT
      LAYER metal2 ;
      RECT 87.745 0.000 87.815 0.210 ;
    END
  END rw0_rd_out[25]
  PIN rw0_rd_out[26]
    DIRECTION OUTPUT ;
    USE SIGNAL ;
    SHAPE ABUTMENT ;
    PORT
      LAYER metal2 ;
      RECT 89.265 0.000 89.335 0.210 ;
    END
  END rw0_rd_out[26]
  PIN rw0_rd_out[27]
    DIRECTION OUTPUT ;
    USE SIGNAL ;
    SHAPE ABUTMENT ;
    PORT
      LAYER metal2 ;
      RECT 90.785 0.000 90.855 0.210 ;
    END
  END rw0_rd_out[27]
  PIN rw0_rd_out[28]
    DIRECTION OUTPUT ;
    USE SIGNAL ;
    SHAPE ABUTMENT ;
    PORT
      LAYER metal2 ;
      RECT 92.305 0.000 92.375 0.210 ;
    END
  END rw0_rd_out[28]
  PIN rw0_rd_out[29]
    DIRECTION OUTPUT ;
    USE SIGNAL ;
    SHAPE ABUTMENT ;
    PORT
      LAYER metal2 ;
      RECT 93.825 0.000 93.895 0.210 ;
    END
  END rw0_rd_out[29]
  PIN rw0_rd_out[30]
    DIRECTION OUTPUT ;
    USE SIGNAL ;
    SHAPE ABUTMENT ;
    PORT
      LAYER metal2 ;
      RECT 95.345 0.000 95.415 0.210 ;
    END
  END rw0_rd_out[30]
  PIN rw0_rd_out[31]
    DIRECTION OUTPUT ;
    USE SIGNAL ;
    SHAPE ABUTMENT ;
    PORT
      LAYER metal2 ;
      RECT 96.865 0.000 96.935 0.210 ;
    END
  END rw0_rd_out[31]
  PIN rw0_rd_out[32]
    DIRECTION OUTPUT ;
    USE SIGNAL ;
    SHAPE ABUTMENT ;
    PORT
      LAYER metal2 ;
      RECT 49.745 237.790 49.815 238.000 ;
    END
  END rw0_rd_out[32]
  PIN rw0_rd_out[33]
    DIRECTION OUTPUT ;
    USE SIGNAL ;
    SHAPE ABUTMENT ;
    PORT
      LAYER metal2 ;
      RECT 51.265 237.790 51.335 238.000 ;
    END
  END rw0_rd_out[33]
  PIN rw0_rd_out[34]
    DIRECTION OUTPUT ;
    USE SIGNAL ;
    SHAPE ABUTMENT ;
    PORT
      LAYER metal2 ;
      RECT 52.785 237.790 52.855 238.000 ;
    END
  END rw0_rd_out[34]
  PIN rw0_rd_out[35]
    DIRECTION OUTPUT ;
    USE SIGNAL ;
    SHAPE ABUTMENT ;
    PORT
      LAYER metal2 ;
      RECT 54.305 237.790 54.375 238.000 ;
    END
  END rw0_rd_out[35]
  PIN rw0_rd_out[36]
    DIRECTION OUTPUT ;
    USE SIGNAL ;
    SHAPE ABUTMENT ;
    PORT
      LAYER metal2 ;
      RECT 55.825 237.790 55.895 238.000 ;
    END
  END rw0_rd_out[36]
  PIN rw0_rd_out[37]
    DIRECTION OUTPUT ;
    USE SIGNAL ;
    SHAPE ABUTMENT ;
    PORT
      LAYER metal2 ;
      RECT 57.345 237.790 57.415 238.000 ;
    END
  END rw0_rd_out[37]
  PIN rw0_rd_out[38]
    DIRECTION OUTPUT ;
    USE SIGNAL ;
    SHAPE ABUTMENT ;
    PORT
      LAYER metal2 ;
      RECT 58.865 237.790 58.935 238.000 ;
    END
  END rw0_rd_out[38]
  PIN rw0_rd_out[39]
    DIRECTION OUTPUT ;
    USE SIGNAL ;
    SHAPE ABUTMENT ;
    PORT
      LAYER metal2 ;
      RECT 60.385 237.790 60.455 238.000 ;
    END
  END rw0_rd_out[39]
  PIN rw0_rd_out[40]
    DIRECTION OUTPUT ;
    USE SIGNAL ;
    SHAPE ABUTMENT ;
    PORT
      LAYER metal2 ;
      RECT 61.905 237.790 61.975 238.000 ;
    END
  END rw0_rd_out[40]
  PIN rw0_rd_out[41]
    DIRECTION OUTPUT ;
    USE SIGNAL ;
    SHAPE ABUTMENT ;
    PORT
      LAYER metal2 ;
      RECT 63.425 237.790 63.495 238.000 ;
    END
  END rw0_rd_out[41]
  PIN rw0_rd_out[42]
    DIRECTION OUTPUT ;
    USE SIGNAL ;
    SHAPE ABUTMENT ;
    PORT
      LAYER metal2 ;
      RECT 64.945 237.790 65.015 238.000 ;
    END
  END rw0_rd_out[42]
  PIN rw0_rd_out[43]
    DIRECTION OUTPUT ;
    USE SIGNAL ;
    SHAPE ABUTMENT ;
    PORT
      LAYER metal2 ;
      RECT 66.465 237.790 66.535 238.000 ;
    END
  END rw0_rd_out[43]
  PIN rw0_rd_out[44]
    DIRECTION OUTPUT ;
    USE SIGNAL ;
    SHAPE ABUTMENT ;
    PORT
      LAYER metal2 ;
      RECT 67.985 237.790 68.055 238.000 ;
    END
  END rw0_rd_out[44]
  PIN rw0_rd_out[45]
    DIRECTION OUTPUT ;
    USE SIGNAL ;
    SHAPE ABUTMENT ;
    PORT
      LAYER metal2 ;
      RECT 69.505 237.790 69.575 238.000 ;
    END
  END rw0_rd_out[45]
  PIN rw0_rd_out[46]
    DIRECTION OUTPUT ;
    USE SIGNAL ;
    SHAPE ABUTMENT ;
    PORT
      LAYER metal2 ;
      RECT 71.025 237.790 71.095 238.000 ;
    END
  END rw0_rd_out[46]
  PIN rw0_rd_out[47]
    DIRECTION OUTPUT ;
    USE SIGNAL ;
    SHAPE ABUTMENT ;
    PORT
      LAYER metal2 ;
      RECT 72.545 237.790 72.615 238.000 ;
    END
  END rw0_rd_out[47]
  PIN rw0_rd_out[48]
    DIRECTION OUTPUT ;
    USE SIGNAL ;
    SHAPE ABUTMENT ;
    PORT
      LAYER metal2 ;
      RECT 74.065 237.790 74.135 238.000 ;
    END
  END rw0_rd_out[48]
  PIN rw0_rd_out[49]
    DIRECTION OUTPUT ;
    USE SIGNAL ;
    SHAPE ABUTMENT ;
    PORT
      LAYER metal2 ;
      RECT 75.585 237.790 75.655 238.000 ;
    END
  END rw0_rd_out[49]
  PIN rw0_rd_out[50]
    DIRECTION OUTPUT ;
    USE SIGNAL ;
    SHAPE ABUTMENT ;
    PORT
      LAYER metal2 ;
      RECT 77.105 237.790 77.175 238.000 ;
    END
  END rw0_rd_out[50]
  PIN rw0_rd_out[51]
    DIRECTION OUTPUT ;
    USE SIGNAL ;
    SHAPE ABUTMENT ;
    PORT
      LAYER metal2 ;
      RECT 78.625 237.790 78.695 238.000 ;
    END
  END rw0_rd_out[51]
  PIN rw0_rd_out[52]
    DIRECTION OUTPUT ;
    USE SIGNAL ;
    SHAPE ABUTMENT ;
    PORT
      LAYER metal2 ;
      RECT 80.145 237.790 80.215 238.000 ;
    END
  END rw0_rd_out[52]
  PIN rw0_rd_out[53]
    DIRECTION OUTPUT ;
    USE SIGNAL ;
    SHAPE ABUTMENT ;
    PORT
      LAYER metal2 ;
      RECT 81.665 237.790 81.735 238.000 ;
    END
  END rw0_rd_out[53]
  PIN rw0_rd_out[54]
    DIRECTION OUTPUT ;
    USE SIGNAL ;
    SHAPE ABUTMENT ;
    PORT
      LAYER metal2 ;
      RECT 83.185 237.790 83.255 238.000 ;
    END
  END rw0_rd_out[54]
  PIN rw0_rd_out[55]
    DIRECTION OUTPUT ;
    USE SIGNAL ;
    SHAPE ABUTMENT ;
    PORT
      LAYER metal2 ;
      RECT 84.705 237.790 84.775 238.000 ;
    END
  END rw0_rd_out[55]
  PIN rw0_rd_out[56]
    DIRECTION OUTPUT ;
    USE SIGNAL ;
    SHAPE ABUTMENT ;
    PORT
      LAYER metal2 ;
      RECT 86.225 237.790 86.295 238.000 ;
    END
  END rw0_rd_out[56]
  PIN rw0_rd_out[57]
    DIRECTION OUTPUT ;
    USE SIGNAL ;
    SHAPE ABUTMENT ;
    PORT
      LAYER metal2 ;
      RECT 87.745 237.790 87.815 238.000 ;
    END
  END rw0_rd_out[57]
  PIN rw0_rd_out[58]
    DIRECTION OUTPUT ;
    USE SIGNAL ;
    SHAPE ABUTMENT ;
    PORT
      LAYER metal2 ;
      RECT 89.265 237.790 89.335 238.000 ;
    END
  END rw0_rd_out[58]
  PIN rw0_rd_out[59]
    DIRECTION OUTPUT ;
    USE SIGNAL ;
    SHAPE ABUTMENT ;
    PORT
      LAYER metal2 ;
      RECT 90.785 237.790 90.855 238.000 ;
    END
  END rw0_rd_out[59]
  PIN rw0_rd_out[60]
    DIRECTION OUTPUT ;
    USE SIGNAL ;
    SHAPE ABUTMENT ;
    PORT
      LAYER metal2 ;
      RECT 92.305 237.790 92.375 238.000 ;
    END
  END rw0_rd_out[60]
  PIN rw0_rd_out[61]
    DIRECTION OUTPUT ;
    USE SIGNAL ;
    SHAPE ABUTMENT ;
    PORT
      LAYER metal2 ;
      RECT 93.825 237.790 93.895 238.000 ;
    END
  END rw0_rd_out[61]
  PIN rw0_rd_out[62]
    DIRECTION OUTPUT ;
    USE SIGNAL ;
    SHAPE ABUTMENT ;
    PORT
      LAYER metal2 ;
      RECT 95.345 237.790 95.415 238.000 ;
    END
  END rw0_rd_out[62]
  PIN rw0_rd_out[63]
    DIRECTION OUTPUT ;
    USE SIGNAL ;
    SHAPE ABUTMENT ;
    PORT
      LAYER metal2 ;
      RECT 96.865 237.790 96.935 238.000 ;
    END
  END rw0_rd_out[63]
  PIN rw0_addr_in[0]
    DIRECTION INPUT ;
    USE SIGNAL ;
    SHAPE ABUTMENT ;
    PORT
      LAYER metal3 ;
      RECT 0.000 202.405 0.210 202.475 ;
    END
  END rw0_addr_in[0]
  PIN rw0_addr_in[1]
    DIRECTION INPUT ;
    USE SIGNAL ;
    SHAPE ABUTMENT ;
    PORT
      LAYER metal3 ;
      RECT 0.000 208.705 0.210 208.775 ;
    END
  END rw0_addr_in[1]
  PIN rw0_addr_in[2]
    DIRECTION INPUT ;
    USE SIGNAL ;
    SHAPE ABUTMENT ;
    PORT
      LAYER metal3 ;
      RECT 0.000 215.005 0.210 215.075 ;
    END
  END rw0_addr_in[2]
  PIN rw0_addr_in[3]
    DIRECTION INPUT ;
    USE SIGNAL ;
    SHAPE ABUTMENT ;
    PORT
      LAYER metal3 ;
      RECT 0.000 221.305 0.210 221.375 ;
    END
  END rw0_addr_in[3]
  PIN rw0_addr_in[4]
    DIRECTION INPUT ;
    USE SIGNAL ;
    SHAPE ABUTMENT ;
    PORT
      LAYER metal3 ;
      RECT 0.000 227.605 0.210 227.675 ;
    END
  END rw0_addr_in[4]
  PIN rw0_addr_in[5]
    DIRECTION INPUT ;
    USE SIGNAL ;
    SHAPE ABUTMENT ;
    PORT
      LAYER metal3 ;
      RECT 109.800 202.405 110.010 202.475 ;
    END
  END rw0_addr_in[5]
  PIN rw0_addr_in[6]
    DIRECTION INPUT ;
    USE SIGNAL ;
    SHAPE ABUTMENT ;
    PORT
      LAYER metal3 ;
      RECT 109.800 208.705 110.010 208.775 ;
    END
  END rw0_addr_in[6]
  PIN rw0_addr_in[7]
    DIRECTION INPUT ;
    USE SIGNAL ;
    SHAPE ABUTMENT ;
    PORT
      LAYER metal3 ;
      RECT 109.800 215.005 110.010 215.075 ;
    END
  END rw0_addr_in[7]
  PIN rw0_addr_in[8]
    DIRECTION INPUT ;
    USE SIGNAL ;
    SHAPE ABUTMENT ;
    PORT
      LAYER metal3 ;
      RECT 109.800 221.305 110.010 221.375 ;
    END
  END rw0_addr_in[8]
  PIN rw0_we_in
    DIRECTION INPUT ;
    USE SIGNAL ;
    SHAPE ABUTMENT ;
    PORT
      LAYER metal2 ;
      RECT 98.385 237.790 98.455 238.000 ;
    END
  END rw0_we_in
  PIN rw0_ce_in
    DIRECTION INPUT ;
    USE SIGNAL ;
    SHAPE ABUTMENT ;
    PORT
      LAYER metal2 ;
      RECT 99.905 237.790 99.975 238.000 ;
    END
  END rw0_ce_in
  PIN rw0_clk
    DIRECTION INPUT ;
    USE SIGNAL ;
    SHAPE ABUTMENT ;
    PORT
      LAYER metal2 ;
      RECT 101.425 237.790 101.495 238.000 ;
    END
  END rw0_clk
  PIN VSS
    DIRECTION INOUT ;
    USE GROUND ;
    PORT
      LAYER metal4 ;
      RECT 1.000 0.840 1.280 237.160 ;
      RECT 3.240 0.840 3.520 237.160 ;
      RECT 5.480 0.840 5.760 237.160 ;
      RECT 7.720 0.840 8.000 237.160 ;
      RECT 9.960 0.840 10.240 237.160 ;
      RECT 12.200 0.840 12.480 237.160 ;
      RECT 14.440 0.840 14.720 237.160 ;
      RECT 16.680 0.840 16.960 237.160 ;
      RECT 18.920 0.840 19.200 237.160 ;
      RECT 21.160 0.840 21.440 237.160 ;
      RECT 23.400 0.840 23.680 237.160 ;
      RECT 25.640 0.840 25.920 237.160 ;
      RECT 27.880 0.840 28.160 237.160 ;
      RECT 30.120 0.840 30.400 237.160 ;
      RECT 32.360 0.840 32.640 237.160 ;
      RECT 34.600 0.840 34.880 237.160 ;
      RECT 36.840 0.840 37.120 237.160 ;
      RECT 39.080 0.840 39.360 237.160 ;
      RECT 41.320 0.840 41.600 237.160 ;
      RECT 43.560 0.840 43.840 237.160 ;
      RECT 45.800 0.840 46.080 237.160 ;
      RECT 48.040 0.840 48.320 237.160 ;
      RECT 50.280 0.840 50.560 237.160 ;
      RECT 52.520 0.840 52.800 237.160 ;
      RECT 54.760 0.840 55.040 237.160 ;
      RECT 57.000 0.840 57.280 237.160 ;
      RECT 59.240 0.840 59.520 237.160 ;
      RECT 61.480 0.840 61.760 237.160 ;
      RECT 63.720 0.840 64.000 237.160 ;
      RECT 65.960 0.840 66.240 237.160 ;
      RECT 68.200 0.840 68.480 237.160 ;
      RECT 70.440 0.840 70.720 237.160 ;
      RECT 72.680 0.840 72.960 237.160 ;
      RECT 74.920 0.840 75.200 237.160 ;
      RECT 77.160 0.840 77.440 237.160 ;
      RECT 79.400 0.840 79.680 237.160 ;
      RECT 81.640 0.840 81.920 237.160 ;
      RECT 83.880 0.840 84.160 237.160 ;
      RECT 86.120 0.840 86.400 237.160 ;
      RECT 88.360 0.840 88.640 237.160 ;
      RECT 90.600 0.840 90.880 237.160 ;
      RECT 92.840 0.840 93.120 237.160 ;
      RECT 95.080 0.840 95.360 237.160 ;
      RECT 97.320 0.840 97.600 237.160 ;
      RECT 99.560 0.840 99.840 237.160 ;
      RECT 101.800 0.840 102.080 237.160 ;
      RECT 104.040 0.840 104.320 237.160 ;
      RECT 106.280 0.840 106.560 237.160 ;
      RECT 108.520 0.840 108.800 237.160 ;
    END
  END VSS
  PIN VDD
    DIRECTION INOUT ;
    USE POWER ;
    PORT
      LAYER metal4 ;
      RECT 2.120 0.840 2.400 237.160 ;
      RECT 4.360 0.840 4.640 237.160 ;
      RECT 6.600 0.840 6.880 237.160 ;
      RECT 8.840 0.840 9.120 237.160 ;
      RECT 11.080 0.840 11.360 237.160 ;
      RECT 13.320 0.840 13.600 237.160 ;
      RECT 15.560 0.840 15.840 237.160 ;
      RECT 17.800 0.840 18.080 237.160 ;
      RECT 20.040 0.840 20.320 237.160 ;
      RECT 22.280 0.840 22.560 237.160 ;
      RECT 24.520 0.840 24.800 237.160 ;
      RECT 26.760 0.840 27.040 237.160 ;
      RECT 29.000 0.840 29.280 237.160 ;
      RECT 31.240 0.840 31.520 237.160 ;
      RECT 33.480 0.840 33.760 237.160 ;
      RECT 35.720 0.840 36.000 237.160 ;
      RECT 37.960 0.840 38.240 237.160 ;
      RECT 40.200 0.840 40.480 237.160 ;
      RECT 42.440 0.840 42.720 237.160 ;
      RECT 44.680 0.840 44.960 237.160 ;
      RECT 46.920 0.840 47.200 237.160 ;
      RECT 49.160 0.840 49.440 237.160 ;
      RECT 51.400 0.840 51.680 237.160 ;
      RECT 53.640 0.840 53.920 237.160 ;
      RECT 55.880 0.840 56.160 237.160 ;
      RECT 58.120 0.840 58.400 237.160 ;
      RECT 60.360 0.840 60.640 237.160 ;
      RECT 62.600 0.840 62.880 237.160 ;
      RECT 64.840 0.840 65.120 237.160 ;
      RECT 67.080 0.840 67.360 237.160 ;
      RECT 69.320 0.840 69.600 237.160 ;
      RECT 71.560 0.840 71.840 237.160 ;
      RECT 73.800 0.840 74.080 237.160 ;
      RECT 76.040 0.840 76.320 237.160 ;
      RECT 78.280 0.840 78.560 237.160 ;
      RECT 80.520 0.840 80.800 237.160 ;
      RECT 82.760 0.840 83.040 237.160 ;
      RECT 85.000 0.840 85.280 237.160 ;
      RECT 87.240 0.840 87.520 237.160 ;
      RECT 89.480 0.840 89.760 237.160 ;
      RECT 91.720 0.840 92.000 237.160 ;
      RECT 93.960 0.840 94.240 237.160 ;
      RECT 96.200 0.840 96.480 237.160 ;
      RECT 98.440 0.840 98.720 237.160 ;
      RECT 100.680 0.840 100.960 237.160 ;
      RECT 102.920 0.840 103.200 237.160 ;
      RECT 105.160 0.840 105.440 237.160 ;
      RECT 107.400 0.840 107.680 237.160 ;
      RECT 109.640 0.840 109.920 237.160 ;
    END
  END VDD
  OBS
    LAYER metal1 ;
    RECT 0 0 110.010 238.000 ;
    LAYER metal2 ;
    RECT 0 0 110.010 238.000 ;
    LAYER metal3 ;
    RECT 0 0 110.010 238.000 ;
    LAYER metal4 ;
    RECT 0 0 110.010 238.000 ;
    LAYER OVERLAP ;
    RECT 0 0 110.010 238.000 ;
  END
END fakeram_512x64_1rw

END LIBRARY
